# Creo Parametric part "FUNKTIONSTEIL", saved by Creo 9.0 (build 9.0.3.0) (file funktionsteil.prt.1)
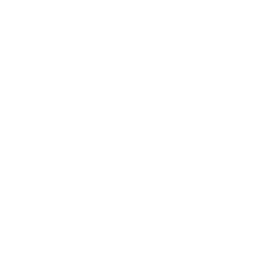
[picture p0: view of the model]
Units: millimeter Kilogram Sec (mmKs); MM, KILOGRAM, SECS
Materials in the file: S235JRG2

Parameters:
  BENENNUNG = "XXX"
  DATUM = "XX.XX.XX"
  ERSTELLER = "ARINDA"
  TEILETYP = "Fertigungsteil"
  PTC_MASTER_MATERIAL = "S235JRG2"
  SELECT_EN_NAME = "S235JRG2"
  SELECT_DIN_NAME = "RSt37-2"
  SELECT_DIN_NUMBER = "1.0038"
  SELECT_ASTM_NAME = "A 283 M Grade 2"
  MATERIAL_GROUP = "ME_ST_Baustahl"
  STANDARD_EN_DELIVERYSPEC = "DIN EN 10025"
  STANDARD_DIN_DELIVERYSPEC = "DIN 17100"

Other parameters: MASSE

Created from: ARINDA-STARTTEIL.PRT

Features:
  1. coordinate system "CS0"
  2. datum plane "DTM1", "T_RECHTS_Y-Z"
  3. datum plane "DTM2", "T_OBEN_X-Z"
  4. datum plane "DTM3", "T_VORNE_X-Y"
  5. datum axis "T_X-ACHSE"
  6. datum axis "A_1"
  7. datum axis "A_2"

Other named items: T_BASIC, T_Y-ACHSE, T_Z-ACHSE

Layers: 00_STD-ACHSEN, 00_STD-EBENEN, 00_STD-KOORDSYS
